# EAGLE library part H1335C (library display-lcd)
LCD DISPLAY 6-character 7 segment

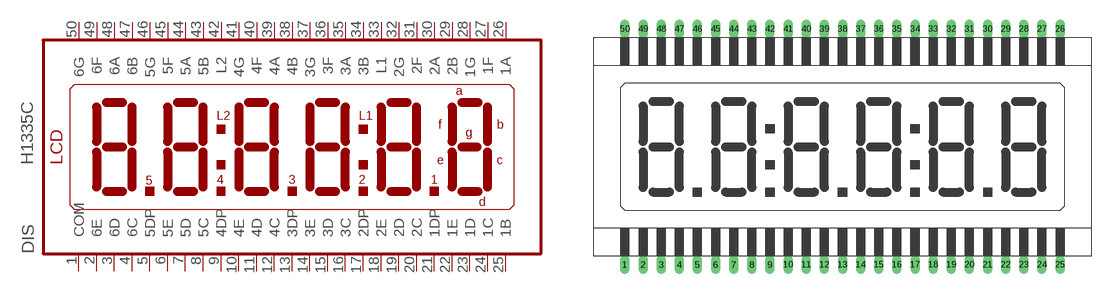
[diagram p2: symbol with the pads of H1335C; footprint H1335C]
Designator prefix DIS

## H1335C (OC_FARNELL: unknown; OC_NEWARK: unknown)  [H1335C]
1  COM  pas
2  6E  pas
3  6D  pas
4  6C  pas
5  5DP  pas
6  5E  pas
7  5D  pas
8  5C  pas
9  4DP  pas
10  4E  pas
11  4D  pas
12  4C  pas
13  3DP  pas
14  3E  pas
15  3D  pas
16  3C  pas
17  2DP  pas
18  2E  pas
19  2D  pas
20  2C  pas
21  1DP  pas
22  1E  pas
23  1D  pas
24  1C  pas
25  1B  pas
26  1A  pas
27  1F  pas
28  1G  pas
29  2B  pas
30  2A  pas
31  2F  pas
32  2G  pas
33  L1  pas
34  3B  pas
35  3A  pas
36  3F  pas
37  3G  pas
38  4B  pas
39  4A  pas
40  4F  pas
41  4G  pas
42  L2  pas
43  5B  pas
44  5A  pas
45  5F  pas
46  5G  pas
47  6B  pas
48  6A  pas
49  6F  pas
50  6G  pas

## Footprint H1335C (pad centres in mm)
LCD DISPLAY 6-character 7 segment
drill 0.813 long: 1 -30.48,-16.51; 2 -27.94,-16.51; 3 -25.4,-16.51; 4 -22.86,-16.51; 5 -20.32,-16.51; 6 -17.78,-16.51; 7 -15.24,-16.51; 8 -12.7,-16.51; 9 -10.16,-16.51; 10 -7.62,-16.51; 11 -5.08,-16.51; 12 -2.54,-16.51; 13 0,-16.51; 14 2.54,-16.51; 15 5.08,-16.51; 16 7.62,-16.51; 17 10.16,-16.51; 18 12.7,-16.51; 19 15.24,-16.51; 20 17.78,-16.51; 21 20.32,-16.51; 22 22.86,-16.51; 23 25.4,-16.51; 24 27.94,-16.51; 25 30.48,-16.51; 26 30.48,16.51; 27 27.94,16.51; 28 25.4,16.51; 29 22.86,16.51; 30 20.32,16.51; 31 17.78,16.51; 32 15.24,16.51; 33 12.7,16.51; 34 10.16,16.51; 35 7.62,16.51; 36 5.08,16.51; 37 2.54,16.51; 38 0,16.51; 39 -2.54,16.51; 40 -5.08,16.51; 41 -7.62,16.51; 42 -10.16,16.51; 43 -12.7,16.51; 44 -15.24,16.51; 45 -17.78,16.51; 46 -20.32,16.51; 47 -22.86,16.51; 48 -25.4,16.51; 49 -27.94,16.51; 50 -30.48,16.51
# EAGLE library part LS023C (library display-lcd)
LCD DISPLAY 4 1/2-character 7 segment

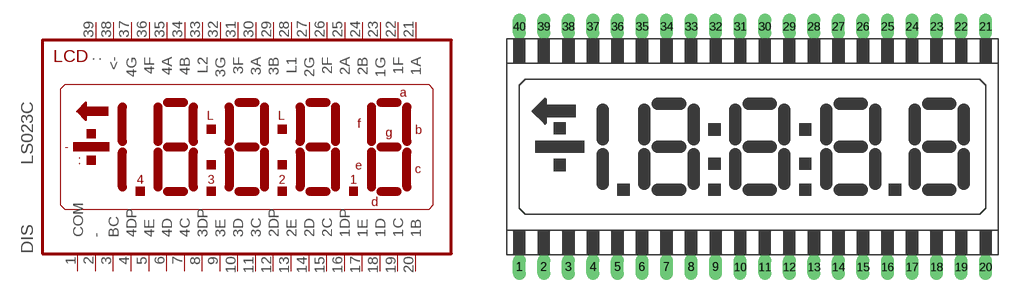
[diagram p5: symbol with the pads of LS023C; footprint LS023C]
Designator prefix DIS

## LS023C (OC_FARNELL: unknown; OC_NEWARK: unknown)  [LS023C]
1  COM  pas
2  -  pas
3  BC  pas
4  4DP  pas
5  4E  pas
6  4D  pas
7  4C  pas
8  3DP  pas
9  3E  pas
10  3D  pas
11  3C  pas
12  2DP  pas
13  2E  pas
14  2D  pas
15  2C  pas
16  1DP  pas
17  1E  pas
18  1D  pas
19  1C  pas
20  1B  pas
21  1A  pas
22  1F  pas
23  1G  pas
24  2B  pas
25  2A  pas
26  2F  pas
27  2G  pas
28  L1  pas
29  3B  pas
30  3A  pas
31  3F  pas
32  3G  pas
33  L2  pas
34  4B  pas
35  4A  pas
36  4F  pas
37  4G  pas
38  <-  pas
39  :  pas

## Footprint LS023C (pad centres in mm)
LCD DISPLAY 4 1/2-character 7 segment
drill 0.813 long: 1 -24.13,-12.446; 2 -21.59,-12.446; 3 -19.05,-12.446; 4 -16.51,-12.446; 5 -13.97,-12.446; 6 -11.43,-12.446; 7 -8.89,-12.446; 8 -6.35,-12.446; 9 -3.81,-12.446; 10 -1.27,-12.446; 11 1.27,-12.446; 12 3.81,-12.446; 13 6.35,-12.446; 14 8.89,-12.446; 15 11.43,-12.446; 16 13.97,-12.446; 17 16.51,-12.446; 18 19.05,-12.446; 19 21.59,-12.446; 20 24.13,-12.446; 21 24.13,12.446; 22 21.59,12.446; 23 19.05,12.446; 24 16.51,12.446; 25 13.97,12.446; 26 11.43,12.446; 27 8.89,12.446; 28 6.35,12.446; 29 3.81,12.446; 30 1.27,12.446; 31 -1.27,12.446; 32 -3.81,12.446; 33 -6.35,12.446; 34 -8.89,12.446; 35 -11.43,12.446; 36 -13.97,12.446; 37 -16.51,12.446; 38 -19.05,12.446; 39 -21.59,12.446; 40 -24.13,12.446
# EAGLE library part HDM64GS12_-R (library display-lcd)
HDM64GS12_-R 128 X 64 Dots Graphic Source: http://www.hantronix.com/down/64gs12-r.pdf

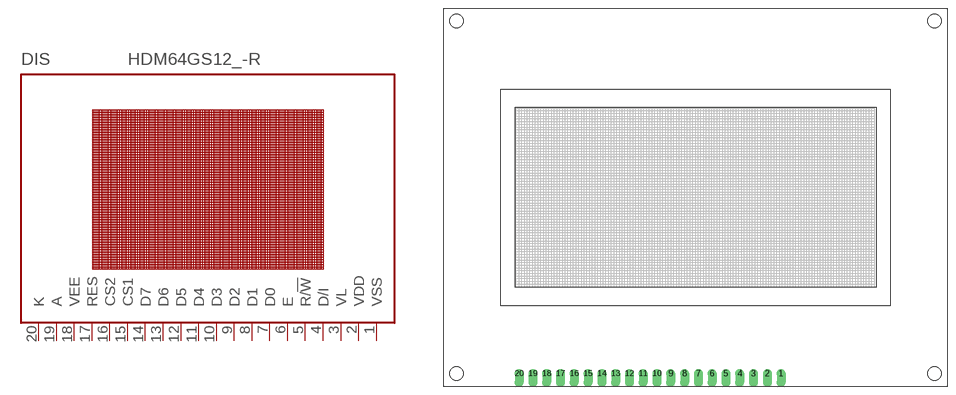
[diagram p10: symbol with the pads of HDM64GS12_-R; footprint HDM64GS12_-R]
Designator prefix DIS

## HDM64GS12_-R (OC_FARNELL: unknown; OC_NEWARK: unknown)  [HDM64GS12_-R]
1  VSS  pwr
2  VDD  pwr
3  VL  pas
4  D/I  in
5  R/!W  in
6  E  in
7  D0
8  D1
9  D2
10  D3
11  D4
12  D5
13  D6
14  D7
15  CS1  in
16  CS2  in
17  RES  in
18  VEE  out
19  A  pas
20  K  pas

## Footprint HDM64GS12_-R (pad centres in mm)
HDM64GS12_-R 128 X 64 Dots Graphic Source: http://www.hantronix.com/down/64gs12-r.pdf
drill 1.1 offset: 1 15.76,-32.5; 2 13.22,-32.5; 3 10.68,-32.5; 4 8.14,-32.5; 5 5.6,-32.5; 6 3.06,-32.5; 7 0.52,-32.5; 8 -2.02,-32.5; 9 -4.56,-32.5; 10 -7.1,-32.5; 11 -9.64,-32.5; 12 -12.18,-32.5; 13 -14.72,-32.5; 14 -17.26,-32.5; 15 -19.8,-32.5; 16 -22.34,-32.5; 17 -24.88,-32.5; 18 -27.42,-32.5; 19 -29.96,-32.5; 20 -32.5,-32.5
hole 2.5 at -44,-32.5
hole 2.5 at 44,-32.5
hole 2.5 at -44,32.5
hole 2.5 at 44,32.5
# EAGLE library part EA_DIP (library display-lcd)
LCD-MODUL 2x16 - 6,68mm, INKL. KONTROLLER HD44780 Source: Data sheet

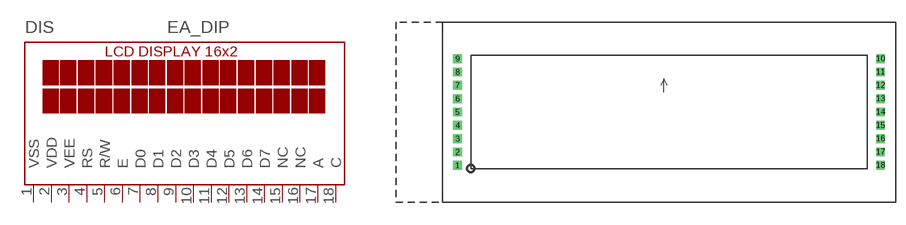
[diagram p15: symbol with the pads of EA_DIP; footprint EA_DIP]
Designator prefix DIS

## EA_DIP  [EA_DIP]
1  VSS  pwr
2  VDD  pwr
3  VEE  pwr
4  RS  in
5  R/W  in
6  E  in
7  D0  in
8  D1  in
9  D2  in
10  D3  in
11  D4  in
12  D5  in
13  D6  in
14  D7  in
15  NC  nc
16  NC  nc
17  A  pas
18  C  pas

## Footprint EA_DIP (pad centres in mm)
LCD-MODUL 2x16 - 6,68mm, INKL. KONTROLLER HD44780 Source: Data sheet
drill 0.813 pad 1.27 square: 1 0,0; 2 0,2; 3 0,4; 4 0,6; 5 0,8; 6 0,10; 7 0,12; 8 0,14; 9 0,16; 10 63.5,16; 11 63.5,14; 12 63.5,12; 13 63.5,10; 14 63.5,8; 15 63.5,6; 16 63.5,4; 17 63.5,2; 18 63.5,0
